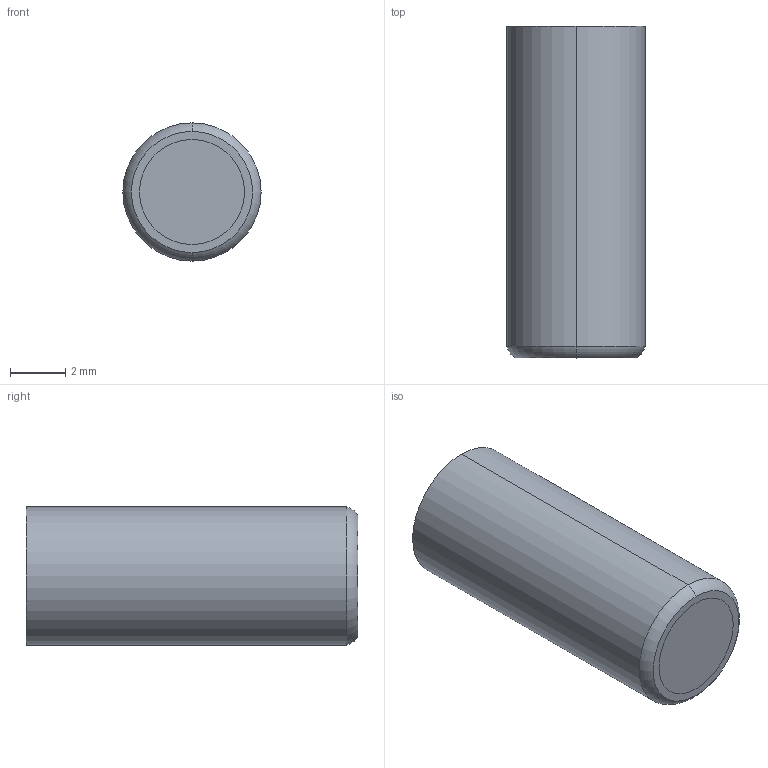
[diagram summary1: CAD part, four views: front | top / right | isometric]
STEP (ISO 10303-21) file: header records copied from the file, then geometry measured from it (millimetres).
FILE_DESCRIPTION (( 'STEP AP214' ), '1' );
FILE_NAME ('FA053000.STEP', '2013-06-28T07:19:33', ( '' ), ( '' ), 'SwSTEP 2.0', 'SolidWorks 2011', '' );
FILE_SCHEMA (( 'AUTOMOTIVE_DESIGN' ));
Length unit declared in the file: millimetre
Products named in the file (6): FA 053000-1; FA 053000-2; 9FA 053000; FA 042200-3; FA053000; IA 3075SF
Assembly tree (5 placements, depth 2):
  FA053000
    9FA 053000
    IA 3075SF
    FA 042200-3
    FA 053000-1
    FA 053000-2
Bounding box: 5 x 12 x 5 mm (x, y, z)
Volume: 204.8 mm3; surface area: 596.4 mm2
Topology: 5 solids, 5 shells, 81 faces, 164 edges, 104 vertices
Faces by surface type: cylinder 34, plane 29, cone 12, bspline 4, torus 2
Entity records: 4452 total; most frequent: CARTESIAN_POINT 2373, DIRECTION 412, ORIENTED_EDGE 328, AXIS2_PLACEMENT_3D 173, EDGE_CURVE 164, VERTEX_POINT 104, EDGE_LOOP 96, CIRCLE 88
One B-rep face of a CAD part: STEP entity #3930.
In plain terms, the planar face has unit normal (0, 1, 0).
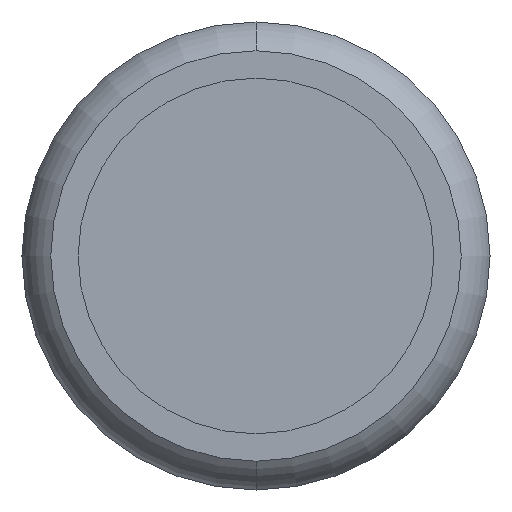
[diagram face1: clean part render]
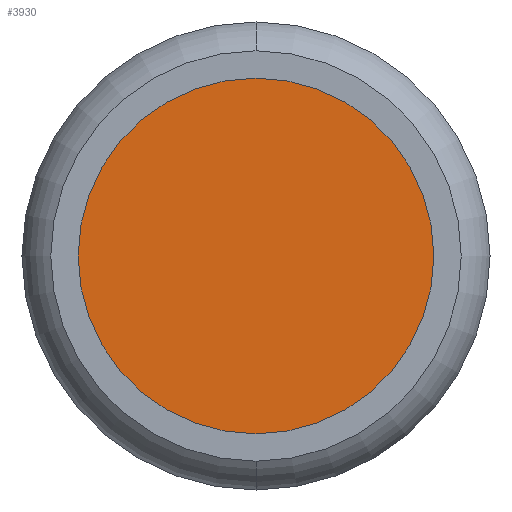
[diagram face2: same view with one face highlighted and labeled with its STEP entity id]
Its self-contained STEP definition (entity closure, numbers rounded to 3 decimals):
#1003 = CARTESIAN_POINT ( 'NONE',  ( 0., 2.45, 0. ) ) ;
#1008 = DIRECTION ( 'NONE',  ( 0., -1., 0. ) ) ;
#1022 = DIRECTION ( 'NONE',  ( 0., 0., -1. ) ) ;
#1133 = DIRECTION ( 'NONE',  ( 0., 0., -1. ) ) ;
#1141 = DIRECTION ( 'NONE',  ( 0., -1., 0. ) ) ;
#1176 = CARTESIAN_POINT ( 'NONE',  ( 0., 2.45, 0. ) ) ;
#1269 = AXIS2_PLACEMENT_3D ( 'NONE', #3541, #3539, #3542 ) ;
#1372 = EDGE_CURVE ( 'NONE', #2242, #2208, #3717, .T. ) ;
#1396 = EDGE_CURVE ( 'NONE', #2208, #2242, #3740, .T. ) ;
#2208 = VERTEX_POINT ( 'NONE', #4167 ) ;
#2242 = VERTEX_POINT ( 'NONE', #4152 ) ;
#2424 = EDGE_LOOP ( 'NONE', ( #2668, #2684 ) ) ;
#2668 = ORIENTED_EDGE ( 'NONE', *, *, #1372, .F. ) ;
#2684 = ORIENTED_EDGE ( 'NONE', *, *, #1396, .F. ) ;
#3521 = FACE_OUTER_BOUND ( 'NONE', #2424, .T. ) ;
#3539 = DIRECTION ( 'NONE',  ( 0., -1., 0. ) ) ;
#3541 = CARTESIAN_POINT ( 'NONE',  ( -2.192, 2.45, 10. ) ) ;
#3542 = DIRECTION ( 'NONE',  ( 0., 0., -1. ) ) ;
#3555 = PLANE ( 'NONE',  #1269 ) ;
#3602 = AXIS2_PLACEMENT_3D ( 'NONE', #1003, #1008, #1022 ) ;
#3717 = CIRCLE ( 'NONE', #3724, 1.9 ) ;
#3724 = AXIS2_PLACEMENT_3D ( 'NONE', #1176, #1141, #1133 ) ;
#3740 = CIRCLE ( 'NONE', #3602, 1.9 ) ;
#3930 = ADVANCED_FACE ( 'NONE', ( #3521 ), #3555, .F. ) ;
#4152 = CARTESIAN_POINT ( 'NONE',  ( 0., 2.45, 1.9 ) ) ;
#4167 = CARTESIAN_POINT ( 'NONE',  ( 0., 2.45, -1.9 ) ) ;
